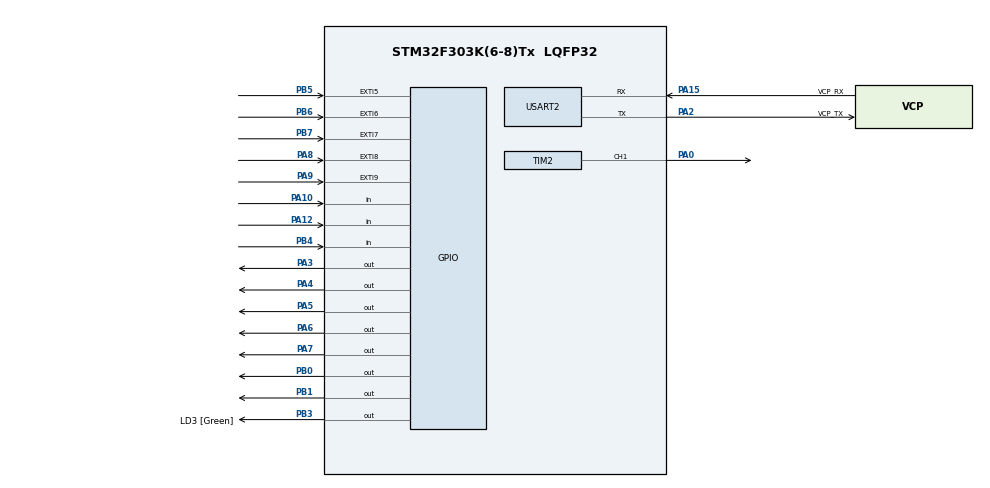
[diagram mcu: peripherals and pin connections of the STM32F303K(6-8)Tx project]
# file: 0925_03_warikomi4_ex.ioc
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Mcu.Family=STM32F3
Mcu.Name=STM32F303K(6-8)Tx
Mcu.Package=LQFP32
NVIC.EXTI9_5_IRQn=true\:1\:0\:true\:false\:true\:true\:true
NVIC.PriorityGroup=NVIC_PRIORITYGROUP_4
PA0.Signal=S_TIM2_CH1_ETR
PA10.GPIO_PuPd=GPIO_PULLDOWN
PA10.Signal=GPIO_Input
PA12.GPIO_PuPd=GPIO_PULLDOWN
PA12.Signal=GPIO_Input
PA13.GPIO_Label=SWDIO
PA13.Mode=Serial_Wire
PA13.Signal=SYS_JTMS-SWDIO
PA14.GPIO_Label=SWCLK
PA14.Mode=Serial_Wire
PA14.Signal=SYS_JTCK-SWCLK
PA15.GPIO_Label=VCP_RX
PA15.Mode=Asynchronous
PA15.Signal=USART2_RX
PA2.GPIO_Label=VCP_TX
PA2.Mode=Asynchronous
PA2.Signal=USART2_TX
PA3.Signal=GPIO_Output
PA4.Signal=GPIO_Output
PA5.Signal=GPIO_Output
PA6.Signal=GPIO_Output
PA7.Signal=GPIO_Output
PA8.GPIO_PuPd=GPIO_PULLDOWN
PA8.Signal=GPXTI8
PA9.GPIO_PuPd=GPIO_PULLDOWN
PA9.Signal=GPXTI9
PB0.Signal=GPIO_Output
PB1.Signal=GPIO_Output
PB3.GPIO_Label=LD3 [Green]
PB3.Signal=GPIO_Output
PB4.GPIO_PuPd=GPIO_PULLDOWN
PB4.Signal=GPIO_Input
PB5.GPIO_PuPd=GPIO_PULLDOWN
PB5.Signal=GPXTI5
PB6.GPIO_PuPd=GPIO_PULLDOWN
PB6.Signal=GPXTI6
PB7.GPIO_PuPd=GPIO_PULLDOWN
PB7.Signal=GPXTI7
PF0\ /\ OSC_IN.GPIO_Label=MCO
PF0\ /\ OSC_IN.Mode=HSE-External-Clock-Source
PF0\ /\ OSC_IN.Signal=RCC_OSC_IN
ProjectManager.HeapSize=0x200
ProjectManager.StackSize=0x400
ProjectManager.TargetToolchain=STM32CubeIDE
RCC.AHBFreq_Value=72000000
RCC.APB1CLKDivider=RCC_HCLK_DIV2
RCC.APB1Freq_Value=36000000
RCC.APB1TimFreq_Value=72000000
RCC.APB2Freq_Value=72000000
RCC.APB2TimFreq_Value=72000000
RCC.CortexFreq_Value=72000000
RCC.HCLKFreq_Value=72000000
RCC.HSE_VALUE=8000000
RCC.HSI_VALUE=8000000
RCC.PLLMUL=RCC_PLL_MUL9
RCC.PLLSourceVirtual=RCC_PLLSOURCE_HSE
RCC.SYSCLKFreq_VALUE=72000000
RCC.SYSCLKSourceVirtual=RCC_SYSCLKSOURCE_PLLCLK
SH.S_TIM2_CH1_ETR.0=TIM2_CH1,PWM Generation1 CH1
TIM2.Channel-PWM\ Generation1\ CH1=TIM_CHANNEL_1
TIM2.Period=999
TIM2.Prescaler=699
USART2.VirtualMode-Asynchronous=VM_ASYNC
VP_TIM2_VS_ClockSourceINT.Mode=Internal
board=NUCLEO-F303K8

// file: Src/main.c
/* USER CODE BEGIN Header */
/**
  ******************************************************************************
  * @file           : main.c
  * @brief          : Main program body
  ******************************************************************************
  * @attention
  *
  * <h2><center>&copy; Copyright (c) 2019 STMicroelectronics.
  * All rights reserved.</center></h2>
  *
  * This software component is licensed by ST under BSD 3-Clause license,
  * the "License"; You may not use this file except in compliance with the
  * License. You may obtain a copy of the License at:
  *                        opensource.org/licenses/BSD-3-Clause
  *
  ******************************************************************************
  */
/* USER CODE END Header */

#include "main.h"

TIM_HandleTypeDef htim2;

UART_HandleTypeDef huart2;

void SystemClock_Config(void);
static void MX_GPIO_Init(void);
static void MX_USART2_UART_Init(void);
static void MX_TIM2_Init(void);

int main(void)
{

  /* MCU Configuration--------------------------------------------------------*/

  /* Reset of all peripherals, Initializes the Flash interface and the Systick. */
  HAL_Init();

  /* Configure the system clock */
  SystemClock_Config();

  /* Initialize all configured peripherals */
  MX_GPIO_Init();
  MX_USART2_UART_Init();
  MX_TIM2_Init();
  /* USER CODE BEGIN 2 */
  TIM2->CCER|=TIM_CCER_CC1E;//
  TIM2->CR1|=TIM_CR1_CEN;
  /* USER CODE END 2 */

  /* Infinite loop */
  while (1)
  {

  }
}

void SystemClock_Config(void)
{
  RCC_OscInitTypeDef RCC_OscInitStruct = {0};
  RCC_ClkInitTypeDef RCC_ClkInitStruct = {0};

  /** Initializes the CPU, AHB and APB busses clocks
  */
  RCC_OscInitStruct.OscillatorType = RCC_OSCILLATORTYPE_HSE;
  RCC_OscInitStruct.HSEState = RCC_HSE_BYPASS;
  RCC_OscInitStruct.HSEPredivValue = RCC_HSE_PREDIV_DIV1;
  RCC_OscInitStruct.HSIState = RCC_HSI_ON;
  RCC_OscInitStruct.PLL.PLLState = RCC_PLL_ON;
  RCC_OscInitStruct.PLL.PLLSource = RCC_PLLSOURCE_HSE;
  RCC_OscInitStruct.PLL.PLLMUL = RCC_PLL_MUL5;
  if (HAL_RCC_OscConfig(&RCC_OscInitStruct) != HAL_OK)
  {
    Error_Handler();
  }
  /** Initializes the CPU, AHB and APB busses clocks
  */
  RCC_ClkInitStruct.ClockType = RCC_CLOCKTYPE_HCLK|RCC_CLOCKTYPE_SYSCLK
                              |RCC_CLOCKTYPE_PCLK1|RCC_CLOCKTYPE_PCLK2;
  RCC_ClkInitStruct.SYSCLKSource = RCC_SYSCLKSOURCE_PLLCLK;
  RCC_ClkInitStruct.AHBCLKDivider = RCC_SYSCLK_DIV4;
  RCC_ClkInitStruct.APB1CLKDivider = RCC_HCLK_DIV2;
  RCC_ClkInitStruct.APB2CLKDivider = RCC_HCLK_DIV1;

  if (HAL_RCC_ClockConfig(&RCC_ClkInitStruct, FLASH_LATENCY_0) != HAL_OK)
  {
    Error_Handler();
  }
}

static void MX_TIM2_Init(void)
{

  TIM_ClockConfigTypeDef sClockSourceConfig = {0};
  TIM_MasterConfigTypeDef sMasterConfig = {0};
  TIM_OC_InitTypeDef sConfigOC = {0};

  htim2.Instance = TIM2;
  htim2.Init.Prescaler = 499;
  htim2.Init.CounterMode = TIM_COUNTERMODE_UP;
  htim2.Init.Period = 9999;
  htim2.Init.ClockDivision = TIM_CLOCKDIVISION_DIV1;
  htim2.Init.AutoReloadPreload = TIM_AUTORELOAD_PRELOAD_DISABLE;
  if (HAL_TIM_Base_Init(&htim2) != HAL_OK)
  {
    Error_Handler();
  }
  sClockSourceConfig.ClockSource = TIM_CLOCKSOURCE_INTERNAL;
  if (HAL_TIM_ConfigClockSource(&htim2, &sClockSourceConfig) != HAL_OK)
  {
    Error_Handler();
  }
  if (HAL_TIM_PWM_Init(&htim2) != HAL_OK)
  {
    Error_Handler();
  }
  sMasterConfig.MasterOutputTrigger = TIM_TRGO_RESET;
  sMasterConfig.MasterSlaveMode = TIM_MASTERSLAVEMODE_DISABLE;
  if (HAL_TIMEx_MasterConfigSynchronization(&htim2, &sMasterConfig) != HAL_OK)
  {
    Error_Handler();
  }
  sConfigOC.OCMode = TIM_OCMODE_PWM1;
  sConfigOC.Pulse = 0;
  sConfigOC.OCPolarity = TIM_OCPOLARITY_HIGH;
  sConfigOC.OCFastMode = TIM_OCFAST_DISABLE;
  if (HAL_TIM_PWM_ConfigChannel(&htim2, &sConfigOC, TIM_CHANNEL_1) != HAL_OK)
  {
    Error_Handler();
  }
  HAL_TIM_MspPostInit(&htim2);

}

static void MX_USART2_UART_Init(void)
{

  huart2.Instance = USART2;
  huart2.Init.BaudRate = 38400;
  huart2.Init.WordLength = UART_WORDLENGTH_8B;
  huart2.Init.StopBits = UART_STOPBITS_1;
  huart2.Init.Parity = UART_PARITY_NONE;
  huart2.Init.Mode = UART_MODE_TX_RX;
  huart2.Init.HwFlowCtl = UART_HWCONTROL_NONE;
  huart2.Init.OverSampling = UART_OVERSAMPLING_16;
  huart2.Init.OneBitSampling = UART_ONE_BIT_SAMPLE_DISABLE;
  huart2.AdvancedInit.AdvFeatureInit = UART_ADVFEATURE_NO_INIT;
  if (HAL_UART_Init(&huart2) != HAL_OK)
  {
    Error_Handler();
  }

}

static void MX_GPIO_Init(void)
{
  GPIO_InitTypeDef GPIO_InitStruct = {0};

  /* GPIO Ports Clock Enable */
  __HAL_RCC_GPIOF_CLK_ENABLE();
  __HAL_RCC_GPIOA_CLK_ENABLE();
  __HAL_RCC_GPIOB_CLK_ENABLE();

  /*Configure GPIO pin Output Level */
  HAL_GPIO_WritePin(GPIOA, GPIO_PIN_3|GPIO_PIN_4|GPIO_PIN_5|GPIO_PIN_6
                          |GPIO_PIN_7, GPIO_PIN_RESET);

  /*Configure GPIO pin Output Level */
  HAL_GPIO_WritePin(GPIOB, GPIO_PIN_0|GPIO_PIN_1|LD3_Pin, GPIO_PIN_RESET);

  /*Configure GPIO pins : PA3 PA4 PA5 PA6
                           PA7 */
  GPIO_InitStruct.Pin = GPIO_PIN_3|GPIO_PIN_4|GPIO_PIN_5|GPIO_PIN_6
                          |GPIO_PIN_7;
  GPIO_InitStruct.Mode = GPIO_MODE_OUTPUT_PP;
  GPIO_InitStruct.Pull = GPIO_NOPULL;
  GPIO_InitStruct.Speed = GPIO_SPEED_FREQ_LOW;
  HAL_GPIO_Init(GPIOA, &GPIO_InitStruct);

  /*Configure GPIO pins : PB0 PB1 LD3_Pin */
  GPIO_InitStruct.Pin = GPIO_PIN_0|GPIO_PIN_1|LD3_Pin;
  GPIO_InitStruct.Mode = GPIO_MODE_OUTPUT_PP;
  GPIO_InitStruct.Pull = GPIO_NOPULL;
  GPIO_InitStruct.Speed = GPIO_SPEED_FREQ_LOW;
  HAL_GPIO_Init(GPIOB, &GPIO_InitStruct);

  /*Configure GPIO pins : PA8 PA9 */
  GPIO_InitStruct.Pin = GPIO_PIN_8|GPIO_PIN_9;
  GPIO_InitStruct.Mode = GPIO_MODE_IT_RISING;
  GPIO_InitStruct.Pull = GPIO_PULLDOWN;
  HAL_GPIO_Init(GPIOA, &GPIO_InitStruct);

  /*Configure GPIO pin : PB4 */
  GPIO_InitStruct.Pin = GPIO_PIN_4;
  GPIO_InitStruct.Mode = GPIO_MODE_INPUT;
  GPIO_InitStruct.Pull = GPIO_PULLDOWN;
  HAL_GPIO_Init(GPIOB, &GPIO_InitStruct);

  /*Configure GPIO pins : PB5 PB6 PB7 */
  GPIO_InitStruct.Pin = GPIO_PIN_5|GPIO_PIN_6|GPIO_PIN_7;
  GPIO_InitStruct.Mode = GPIO_MODE_IT_RISING;
  GPIO_InitStruct.Pull = GPIO_PULLDOWN;
  HAL_GPIO_Init(GPIOB, &GPIO_InitStruct);

  /* EXTI interrupt init*/
  HAL_NVIC_SetPriority(EXTI9_5_IRQn, 1, 0);
  HAL_NVIC_EnableIRQ(EXTI9_5_IRQn);

}

void Error_Handler(void)
{
}

/************************ (C) COPYRIGHT STMicroelectronics *****END OF FILE****/
